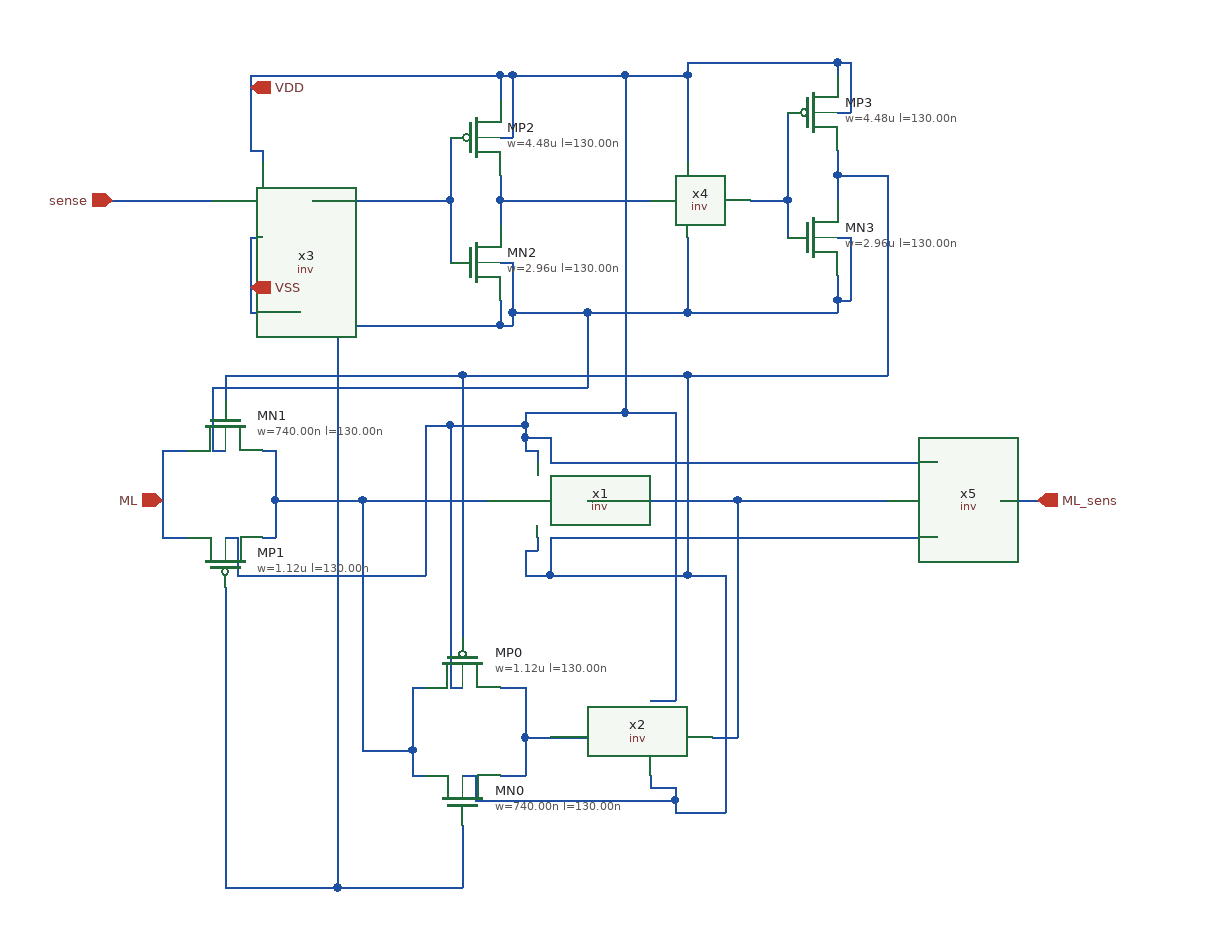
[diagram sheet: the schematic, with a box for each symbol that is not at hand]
v {xschem version=3.4.6 file_version=1.2}
G {}
K {}
V {}
S {}
E {}
N -80 270 -60 270 {lab=#net1}
N -80 340 -60 340 {lab=#net1}
N -150 270 -140 270 {lab=#net2}
N -150 320 -150 340 {lab=#net2}
N -150 340 -140 340 {lab=#net2}
N -110 340 -100 340 {lab=#net3}
N -120 270 -110 270 {lab=VDD}
N -190 120 -90 120 {lab=#net2}
N -60 310 -60 340 {lab=#net1}
N -10 120 110 120 {lab=#net4}
N 110 120 110 310 {lab=#net4}
N 90 310 110 310 {lab=#net4}
N -190 120 -190 320 {lab=#net2}
N -60 70 -60 80 {lab=VDD}
N -110 380 -110 430 {lab=#net5}
N -60 160 -60 180 {lab=#net3}
N 60 360 60 370 {lab=#net3}
N -250 -30 -240 -30 {lab=VSS}
N -390 -120 -310 -120 {lab=sense}
N -350 150 -330 150 {lab=ML}
N -350 80 -330 80 {lab=ML}
N -270 150 -260 150 {lab=#net2}
N -270 80 -260 80 {lab=#net2}
N -310 80 -300 80 {lab=VSS}
N -300 150 -290 150 {lab=VDD}
N -290 150 -290 180 {lab=VDD}
N -300 20 -300 40 {lab=#net3}
N -260 120 -260 150 {lab=#net2}
N -350 80 -350 150 {lab=ML}
N -300 190 -300 430 {lab=#net5}
N -210 -120 -120 -120 {lab=#net5}
N -80 -220 -70 -220 {lab=VDD}
N -80 -170 -70 -170 {lab=VDD}
N -80 -70 -70 -70 {lab=VSS}
N -80 -20 -70 -20 {lab=VSS}
N -120 -120 -120 -70 {lab=#net5}
N -80 -220 -80 -200 {lab=VDD}
N -70 -220 -70 -170 {lab=VDD}
N -70 -30 -70 -20 {lab=VSS}
N -80 -40 -80 -20 {lab=VSS}
N -120 -170 -120 -120 {lab=#net5}
N -250 -20 -80 -20 {lab=VSS}
N -250 -30 -250 -20 {lab=VSS}
N -280 -30 -250 -30 {lab=VSS}
N -280 -220 -280 -160 {lab=VDD}
N -280 -220 -80 -220 {lab=VDD}
N 110 120 230 120 {lab=#net4}
N -260 120 -190 120 {lab=#net2}
N -260 80 -260 120 {lab=#net2}
N -60 310 10 310 {lab=#net1}
N -60 270 -60 310 {lab=#net1}
N -190 320 -150 320 {lab=#net2}
N -150 270 -150 320 {lab=#net2}
N 70 -220 70 -150 {lab=VDD}
N 20 -220 70 -220 {lab=VDD}
N -10 -30 70 -30 {lab=VSS}
N -70 -70 -70 -30 {lab=VSS}
N 190 -40 190 -30 {lab=VSS}
N 70 -30 190 -30 {lab=VSS}
N 190 -90 200 -90 {lab=VSS}
N 200 -90 200 -40 {lab=VSS}
N 190 -40 200 -40 {lab=VSS}
N 190 -60 190 -40 {lab=VSS}
N 70 -230 70 -220 {lab=VDD}
N 70 -230 190 -230 {lab=VDD}
N 190 -230 190 -220 {lab=VDD}
N 190 -190 200 -190 {lab=VDD}
N 200 -230 200 -190 {lab=VDD}
N 190 -230 200 -230 {lab=VDD}
N 190 -140 190 -120 {lab=#net3}
N -80 -120 -80 -100 {lab=#net6}
N -80 -120 40 -120 {lab=#net6}
N -80 -140 -80 -120 {lab=#net6}
N 150 -120 150 -90 {lab=#net7}
N 120 -120 150 -120 {lab=#net7}
N 150 -190 150 -120 {lab=#net7}
N 190 -140 230 -140 {lab=#net3}
N 190 -160 190 -140 {lab=#net3}
N -60 160 -50 160 {lab=#net3}
N -50 150 -50 160 {lab=#net3}
N -60 80 -50 80 {lab=VDD}
N -50 80 -50 90 {lab=VDD}
N 40 280 60 280 {lab=VDD}
N 40 350 60 350 {lab=#net3}
N 40 340 40 350 {lab=#net3}
N -270 -160 -270 -150 {lab=VDD}
N -280 -160 -270 -160 {lab=VDD}
N -280 -90 -280 -30 {lab=VSS}
N -280 -90 -270 -90 {lab=VSS}
N 70 -90 70 -30 {lab=VSS}
N -210 430 -110 430 {lab=#net5}
N -210 -120 -210 430 {lab=#net5}
N -230 -120 -210 -120 {lab=#net5}
N -300 430 -210 430 {lab=#net5}
N -300 20 -110 20 {lab=#net3}
N -110 20 -110 230 {lab=#net3}
N 230 -140 230 20 {lab=#net3}
N 70 20 230 20 {lab=#net3}
N -60 50 20 50 {lab=VDD}
N 20 -220 20 50 {lab=VDD}
N -70 -220 20 -220 {lab=VDD}
N -40 180 70 180 {lab=#net3}
N 70 20 70 180 {lab=#net3}
N -110 20 70 20 {lab=#net3}
N 60 50 60 280 {lab=VDD}
N 20 50 60 50 {lab=VDD}
N 60 370 100 370 {lab=#net3}
N 100 180 100 370 {lab=#net3}
N 70 180 100 180 {lab=#net3}
N -290 180 -140 180 {lab=VDD}
N -140 60 -140 180 {lab=VDD}
N -120 60 -60 60 {lab=VDD}
N -60 50 -60 60 {lab=VDD}
N -310 30 -310 80 {lab=VSS}
N -310 30 -10 30 {lab=VSS}
N -10 -30 -10 30 {lab=VSS}
N -70 -30 -10 -30 {lab=VSS}
N -100 340 -100 360 {lab=#net3}
N -100 360 60 360 {lab=#net3}
N 60 350 60 360 {lab=#net3}
N -120 60 -120 270 {lab=VDD}
N -140 60 -120 60 {lab=VDD}
N 320 120 350 120 {lab=ML_sens}
N -40 90 270 90 {lab=VDD}
N -40 70 -40 90 {lab=VDD}
N -60 70 -40 70 {lab=VDD}
N -60 60 -60 70 {lab=VDD}
N -40 150 270 150 {lab=#net3}
N -40 150 -40 180 {lab=#net3}
N -60 180 -40 180 {lab=#net3}
C {/home/designer/shared/inv.sym} -10 210 0 0 {name=x1}
C {sg13g2_pr/sg13_lv_pmos.sym} -110 250 1 0 {name=MP0
l=130.00n
w=1.12u
ng=1
m=1
model=sg13_lv_pmos
spiceprefix=X
}
C {sg13g2_pr/sg13_lv_nmos.sym} -110 360 3 0 {name=MN0
l=130.00n
w=740.00n
ng=1
m=1
model=sg13_lv_nmos
spiceprefix=X
}
C {sg13g2_pr/sg13_lv_pmos.sym} -300 170 3 0 {name=MP1
l=130.00n
w=1.12u
ng=1
m=1
model=sg13_lv_pmos
spiceprefix=X
}
C {sg13g2_pr/sg13_lv_nmos.sym} -300 60 1 0 {name=MN1
l=130.00n
w=740.00n
ng=1
m=1
model=sg13_lv_nmos
spiceprefix=X
}
C {sg13g2_pr/sg13_lv_nmos.sym} -100 -70 0 0 {name=MN2
l=130.00n
w=2.96u
ng=1
m=1
model=sg13_lv_nmos
spiceprefix=X
}
C {sg13g2_pr/sg13_lv_pmos.sym} -100 -170 0 0 {name=MP2
l=130.00n
w=4.48u
ng=1
m=1
model=sg13_lv_pmos
spiceprefix=X
}
C {sg13g2_pr/sg13_lv_pmos.sym} 170 -190 0 0 {name=MP3
l=130.00n
w=4.48u
ng=1
m=1
model=sg13_lv_pmos
spiceprefix=X
}
C {sg13g2_pr/sg13_lv_nmos.sym} 170 -90 0 0 {name=MN3
l=130.00n
w=2.96u
ng=1
m=1
model=sg13_lv_nmos
spiceprefix=X
}
C {/home/designer/shared/inv.sym} 80 400 0 0 {name=x2}
C {/home/designer/shared/inv.sym} -230 -30 0 0 {name=x3}
C {/home/designer/shared/inv.sym} 110 -30 0 0 {name=x4}
C {ipin.sym} -390 -120 0 0 {name=p2 lab=sense}
C {iopin.sym} -280 -210 0 1 {name=p3 lab=VDD}
C {iopin.sym} -280 -50 0 1 {name=p4 lab=VSS}
C {ipin.sym} -350 120 0 0 {name=p5 lab=ML}
C {/home/designer/shared/inv.sym} 310 210 0 0 {name=x5}
C {opin.sym} 350 120 0 0 {name=p1 lab=ML_sens}
